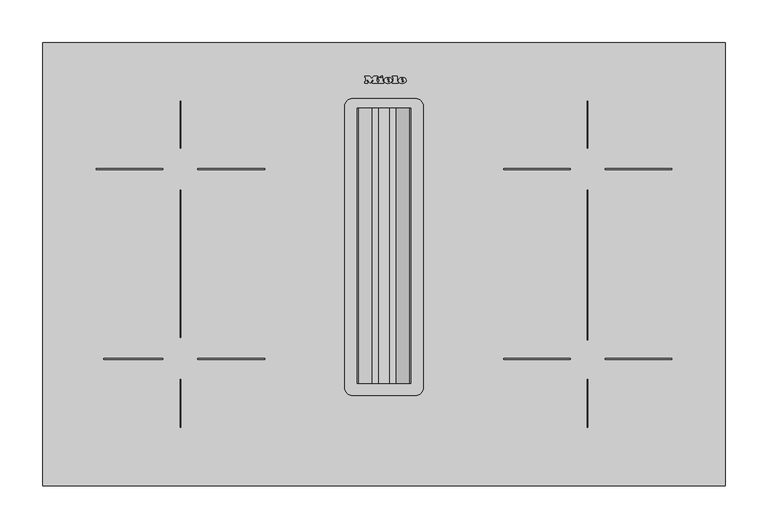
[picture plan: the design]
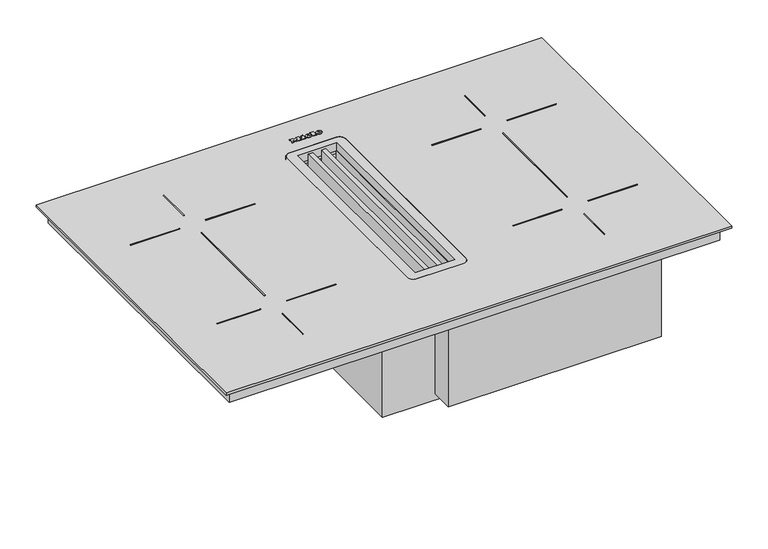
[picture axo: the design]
"""IFC4 building model written with IfcOpenShell, lengths in millimetres: proxy geometry."""

from ifc_helpers import new_model, si_unit, point, frame, frame_2d, origin, origin_with_axes, place, context, project, spatial, polyline, circle_curve, ellipse_curve, trimmed, segment, composite_curve, outline, extrude, faceted_brep, source, transform, mapped, element, save
from ifc_brep_helpers import plane_surface, cylinder_surface, revolved_surface, extruded_surface, advanced_brep


def specialty_equipment_16687752(model_context):
    return source(origin(), model_context, "Body", "SolidModel", [
        advanced_brep(
        [(20.8243124, 474.5406203, 5.0), (20.8243124, 475.3486203, 5.0), (26.1763124, 475.3486203, 5.0), (16.8643124, 475.3486203, 5.0), (19.0643124, 472.6446203, 5.0), (26.0403124, 474.5406203, 5.0), (23.6243124, 474.5406203, 5.0), (21.7203124, 473.6446203, 5.0), (20.8243124, 476.3726203, 5.0), (20.8243124, 477.2446203, 5.0), (22.1923124, 477.2446203, 5.0), (22.1923124, 476.3726203, 5.0), (20.8243124, 474.5406203, 4.0), (21.7203124, 473.6446203, 4.0), (23.6243124, 474.5406203, 4.0), (26.0403124, 474.5406203, 4.0), (19.0643124, 472.6446203, 4.0), (16.8643124, 475.3486203, 4.0), (26.1763124, 475.3486203, 4.0), (20.8243124, 475.3486203, 4.0), (20.8243124, 476.3726203, 4.0), (22.1923124, 476.3726203, 4.0), (22.1923124, 477.2446203, 4.0), (20.8243124, 477.2446203, 4.0)],
        [
            (0, 1),
            (1, 2),
            (2, 3, ellipse_curve(frame((21.5203124, 475.3486203, 5.0), z_axis=(0.0, 0.0, 1.0), x_axis=(-1.0, 0.0, 0.0)), 4.656, 3.848)),
            (3, 4, circle_curve(frame((19.960356, 475.6206203, 5.0), z_axis=(0.0, 0.0, 1.0), x_axis=(0.0, -1.0, 0.0)), 3.1079688)),
            (4, 5, circle_curve(frame((21.4271059, 477.7326203, 5.0), z_axis=(0.0, 0.0, 1.0), x_axis=(0.0, -1.0, 0.0)), 5.6098607)),
            (5, 6),
            (6, 7, circle_curve(frame((22.1113712, 475.2846203, 5.0), z_axis=(0.0, 0.0, -1.0), x_axis=(0.0, -1.0, 0.0)), 1.6859795)),
            (7, 0, circle_curve(frame((21.7203124, 474.5406203, 5.0), z_axis=(0.0, 0.0, -1.0), x_axis=(0.0, -1.0, 0.0)), 0.896)),
            (8, 9),
            (9, 10, circle_curve(frame((21.5083124, 477.2446203, 5.0), z_axis=(0.0, 0.0, -1.0), x_axis=(0.0, -1.0, 0.0)), 0.684)),
            (10, 11),
            (11, 8),
            (12, 13, circle_curve(frame((21.7203124, 474.5406203, 4.0), z_axis=(0.0, 0.0, 1.0), x_axis=(0.0, -1.0, 0.0)), 0.896)),
            (13, 14, circle_curve(frame((22.1113712, 475.2846203, 4.0), z_axis=(0.0, 0.0, 1.0), x_axis=(0.0, -1.0, 0.0)), 1.6859795)),
            (14, 15),
            (15, 16, circle_curve(frame((21.4271059, 477.7326203, 4.0), z_axis=(0.0, 0.0, -1.0), x_axis=(0.0, -1.0, 0.0)), 5.6098607)),
            (16, 17, circle_curve(frame((19.960356, 475.6206203, 4.0), z_axis=(0.0, 0.0, -1.0), x_axis=(0.0, -1.0, 0.0)), 3.1079688)),
            (17, 18, ellipse_curve(frame((21.5203124, 475.3486203, 4.0), z_axis=(0.0, 0.0, -1.0), x_axis=(-1.0, 0.0, 0.0)), 4.656, 3.848)),
            (18, 19),
            (19, 12),
            (20, 21),
            (21, 22),
            (22, 23, circle_curve(frame((21.5083124, 477.2446203, 4.0), z_axis=(0.0, 0.0, 1.0), x_axis=(0.0, -1.0, 0.0)), 0.684)),
            (23, 20),
            (0, 12),
            (19, 1),
            (18, 2),
            (5, 15),
            (14, 6),
            (17, 3),
            (13, 7),
            (16, 4),
            (8, 20),
            (23, 9),
            (22, 10),
            (21, 11),
        ],
        [
            plane_surface(frame((20.8243124, 475.3486203, 5.0), z_axis=(0.0, 0.0, 1.0), x_axis=(0.0, 1.0, 0.0))),
            plane_surface(frame((20.8243124, 475.3486203, 4.0), z_axis=(0.0, 0.0, -1.0), x_axis=(0.0, -1.0, 0.0))),
            plane_surface(frame((20.8243124, 474.5406203, 5.0), z_axis=(1.0, 0.0, 0.0), x_axis=(0.0, 0.0, -1.0))),
            plane_surface(frame((20.8243124, 475.3486203, 5.0), z_axis=(0.0, -1.0, 0.0), x_axis=(0.0, 0.0, -1.0))),
            plane_surface(frame((26.0403124, 474.5406203, 5.0), z_axis=(0.0, 1.0, 0.0), x_axis=(0.0, 0.0, -1.0))),
            extruded_surface(trimmed(ellipse_curve(frame((21.5203124, 475.3486203, 3.0), z_axis=(0.0, 0.0, 1.0), x_axis=(-1.0, 0.0, 0.0)), 4.656, 3.848), [point((26.1763124, 475.3486203, 3.0))], [point((16.8643124, 475.3486203, 3.0))], True, "CARTESIAN"), (0.0, 0.0, 1.0), 1.0),
            revolved_surface(polyline([(22.1113712, 473.5986408, 4.0), (22.1113712, 473.5986408, 5.0)]), (22.1113712, 475.2846203, 4.0), (0.0, 0.0, -1.0)),
            revolved_surface(polyline([(21.7203124, 473.6446203, 4.0), (21.7203124, 473.6446203, 5.0)]), (21.7203124, 474.5406203, 4.0), (0.0, 0.0, -1.0)),
            cylinder_surface(frame((19.960356, 475.6206203, 4.0), z_axis=(0.0, 0.0, 1.0), x_axis=(0.0, -1.0, 0.0)), 3.1079688),
            cylinder_surface(frame((21.4271059, 477.7326203, 4.0), z_axis=(0.0, 0.0, 1.0), x_axis=(0.0, -1.0, 0.0)), 5.6098607),
            plane_surface(frame((20.8243124, 476.3726203, 5.0), z_axis=(1.0, 0.0, 0.0), x_axis=(0.0, 0.0, -1.0))),
            revolved_surface(polyline([(21.5083124, 476.5606203, 4.0), (21.5083124, 476.5606203, 5.0)]), (21.5083124, 477.2446203, 4.0), (0.0, 0.0, -1.0)),
            plane_surface(frame((22.1923124, 477.2446203, 5.0), z_axis=(-1.0, 0.0, 0.0), x_axis=(0.0, 0.0, -1.0))),
            plane_surface(frame((22.1923124, 476.3726203, 5.0), z_axis=(0.0, 1.0, 0.0), x_axis=(0.0, 0.0, -1.0))),
        ],
        [
            (0, [[1, 2, 3, 4, 5, 6, 7, 8], [9, 10, 11, 12]]),
            (1, [[13, 14, 15, 16, 17, 18, 19, 20], [21, 22, 23, 24]]),
            (2, [[-1, 25, -20, 26]]),
            (3, [[-2, -26, -19, 27]]),
            (4, [[-6, 28, -15, 29]]),
            (5, [[-3, -27, -18, 30]]),
            (6, [[-7, -29, -14, 31]]),
            (7, [[-8, -31, -13, -25]]),
            (8, [[-4, -30, -17, 32]]),
            (9, [[-5, -32, -16, -28]]),
            (10, [[-9, 33, -24, 34]]),
            (11, [[-10, -34, -23, 35]]),
            (12, [[-11, -35, -22, 36]]),
            (13, [[-12, -36, -21, -33]]),
        ],
    ),
        advanced_brep(
        [(4.1283124, 474.5406203, 5.0), (4.1283124, 475.3486203, 5.0), (9.4803124, 475.3486203, 5.0), (0.1683124, 475.3486203, 5.0), (2.3683124, 472.6446203, 5.0), (9.3443124, 474.5406203, 5.0), (6.9283124, 474.5406203, 5.0), (5.0243124, 473.6446203, 5.0), (4.1283124, 476.3726203, 5.0), (4.1283124, 477.2446203, 5.0), (5.4963124, 477.2446203, 5.0), (5.4963124, 476.3726203, 5.0), (4.1283124, 474.5406203, 4.0), (5.0243124, 473.6446203, 4.0), (6.9283124, 474.5406203, 4.0), (9.3443124, 474.5406203, 4.0), (2.3683124, 472.6446203, 4.0), (0.1683124, 475.3486203, 4.0), (9.4803124, 475.3486203, 4.0), (4.1283124, 475.3486203, 4.0), (4.1283124, 476.3726203, 4.0), (5.4963124, 476.3726203, 4.0), (5.4963124, 477.2446203, 4.0), (4.1283124, 477.2446203, 4.0)],
        [
            (0, 1),
            (1, 2),
            (2, 3, ellipse_curve(frame((4.8243124, 475.3486203, 5.0), z_axis=(0.0, 0.0, 1.0), x_axis=(-1.0, 0.0, 0.0)), 4.656, 3.848)),
            (3, 4, circle_curve(frame((3.264356, 475.6206203, 5.0), z_axis=(0.0, 0.0, 1.0), x_axis=(0.0, -1.0, 0.0)), 3.1079688)),
            (4, 5, circle_curve(frame((4.7311059, 477.7326203, 5.0), z_axis=(0.0, 0.0, 1.0), x_axis=(0.0, -1.0, 0.0)), 5.6098607)),
            (5, 6),
            (6, 7, circle_curve(frame((5.4153712, 475.2846203, 5.0), z_axis=(0.0, 0.0, -1.0), x_axis=(0.0, -1.0, 0.0)), 1.6859795)),
            (7, 0, circle_curve(frame((5.0243124, 474.5406203, 5.0), z_axis=(0.0, 0.0, -1.0), x_axis=(0.0, -1.0, 0.0)), 0.896)),
            (8, 9),
            (9, 10, circle_curve(frame((4.8123124, 477.2446203, 5.0), z_axis=(0.0, 0.0, -1.0), x_axis=(0.0, -1.0, 0.0)), 0.684)),
            (10, 11),
            (11, 8),
            (12, 13, circle_curve(frame((5.0243124, 474.5406203, 4.0), z_axis=(0.0, 0.0, 1.0), x_axis=(0.0, -1.0, 0.0)), 0.896)),
            (13, 14, circle_curve(frame((5.4153712, 475.2846203, 4.0), z_axis=(0.0, 0.0, 1.0), x_axis=(0.0, -1.0, 0.0)), 1.6859795)),
            (14, 15),
            (15, 16, circle_curve(frame((4.7311059, 477.7326203, 4.0), z_axis=(0.0, 0.0, -1.0), x_axis=(0.0, -1.0, 0.0)), 5.6098607)),
            (16, 17, circle_curve(frame((3.264356, 475.6206203, 4.0), z_axis=(0.0, 0.0, -1.0), x_axis=(0.0, -1.0, 0.0)), 3.1079688)),
            (17, 18, ellipse_curve(frame((4.8243124, 475.3486203, 4.0), z_axis=(0.0, 0.0, -1.0), x_axis=(-1.0, 0.0, 0.0)), 4.656, 3.848)),
            (18, 19),
            (19, 12),
            (20, 21),
            (21, 22),
            (22, 23, circle_curve(frame((4.8123124, 477.2446203, 4.0), z_axis=(0.0, 0.0, 1.0), x_axis=(0.0, -1.0, 0.0)), 0.684)),
            (23, 20),
            (0, 12),
            (19, 1),
            (18, 2),
            (5, 15),
            (14, 6),
            (17, 3),
            (13, 7),
            (16, 4),
            (8, 20),
            (23, 9),
            (22, 10),
            (21, 11),
        ],
        [
            plane_surface(frame((4.1283124, 475.3486203, 5.0), z_axis=(0.0, 0.0, 1.0), x_axis=(0.0, 1.0, 0.0))),
            plane_surface(frame((4.1283124, 475.3486203, 4.0), z_axis=(0.0, 0.0, -1.0), x_axis=(0.0, -1.0, 0.0))),
            plane_surface(frame((4.1283124, 474.5406203, 5.0), z_axis=(1.0, 0.0, 0.0), x_axis=(0.0, 0.0, -1.0))),
            plane_surface(frame((4.1283124, 475.3486203, 5.0), z_axis=(0.0, -1.0, 0.0), x_axis=(0.0, 0.0, -1.0))),
            plane_surface(frame((9.3443124, 474.5406203, 5.0), z_axis=(0.0, 1.0, 0.0), x_axis=(0.0, 0.0, -1.0))),
            extruded_surface(trimmed(ellipse_curve(frame((4.8243124, 475.3486203, 3.0), z_axis=(0.0, 0.0, 1.0), x_axis=(-1.0, 0.0, 0.0)), 4.656, 3.848), [point((9.4803124, 475.3486203, 3.0))], [point((0.1683124, 475.3486203, 3.0))], True, "CARTESIAN"), (0.0, 0.0, 1.0), 1.0),
            revolved_surface(polyline([(5.4153712, 473.5986408, 4.0), (5.4153712, 473.5986408, 5.0)]), (5.4153712, 475.2846203, 4.0), (0.0, 0.0, -1.0)),
            revolved_surface(polyline([(5.0243124, 473.6446203, 4.0), (5.0243124, 473.6446203, 5.0)]), (5.0243124, 474.5406203, 4.0), (0.0, 0.0, -1.0)),
            cylinder_surface(frame((3.264356, 475.6206203, 4.0), z_axis=(0.0, 0.0, 1.0), x_axis=(0.0, -1.0, 0.0)), 3.1079688),
            cylinder_surface(frame((4.7311059, 477.7326203, 4.0), z_axis=(0.0, 0.0, 1.0), x_axis=(0.0, -1.0, 0.0)), 5.6098607),
            plane_surface(frame((4.1283124, 476.3726203, 5.0), z_axis=(1.0, 0.0, 0.0), x_axis=(0.0, 0.0, -1.0))),
            revolved_surface(polyline([(4.8123124, 476.5606203, 4.0), (4.8123124, 476.5606203, 5.0)]), (4.8123124, 477.2446203, 4.0), (0.0, 0.0, -1.0)),
            plane_surface(frame((5.4963124, 477.2446203, 5.0), z_axis=(-1.0, 0.0, 0.0), x_axis=(0.0, 0.0, -1.0))),
            plane_surface(frame((5.4963124, 476.3726203, 5.0), z_axis=(0.0, 1.0, 0.0), x_axis=(0.0, 0.0, -1.0))),
        ],
        [
            (0, [[1, 2, 3, 4, 5, 6, 7, 8], [9, 10, 11, 12]]),
            (1, [[13, 14, 15, 16, 17, 18, 19, 20], [21, 22, 23, 24]]),
            (2, [[-1, 25, -20, 26]]),
            (3, [[-2, -26, -19, 27]]),
            (4, [[-6, 28, -15, 29]]),
            (5, [[-3, -27, -18, 30]]),
            (6, [[-7, -29, -14, 31]]),
            (7, [[-8, -31, -13, -25]]),
            (8, [[-4, -30, -17, 32]]),
            (9, [[-5, -32, -16, -28]]),
            (10, [[-9, 33, -24, 34]]),
            (11, [[-10, -34, -23, 35]]),
            (12, [[-11, -35, -22, 36]]),
            (13, [[-12, -36, -21, -33]]),
        ],
    ),
        extrude(outline(polyline([(-4.6156876, 480.1726203), (-1.8956876, 481.4366203), (-1.2956876, 480.1406203), (-4.0076876, 478.8766203), (-4.6156876, 480.1726203)])), frame((0.0, 0.0, 4.0), z_axis=(0.0, 0.0, 1.0), x_axis=(1.0, 0.0, 0.0)), (0.0, 0.0, 1.0), 1.0),
        extrude(outline(polyline([(-6.5916876, 478.7006203), (-1.2076876, 478.7006203), (-1.2076876, 473.9886203), (-0.2796876, 473.9886203), (-0.2796876, 472.6446203), (-6.5916876, 472.6446203), (-6.5916876, 473.9886203), (-5.6396876, 473.9886203), (-5.6396876, 477.2686203), (-6.5916876, 477.2686203), (-6.5916876, 478.7006203)])), frame((0.0, 0.0, 4.0), z_axis=(0.0, 0.0, 1.0), x_axis=(1.0, 0.0, 0.0)), (0.0, 0.0, 1.0), 1.0),
        extrude(outline(polyline([(9.9283124, 479.3406203), (9.9283124, 480.6446203), (15.4323124, 480.6446203), (15.4323124, 473.9886203), (16.4163124, 473.9886203), (16.4163124, 472.6446203), (9.9283124, 472.6446203), (9.9283124, 473.9886203), (10.8883124, 473.9886203), (10.8883124, 479.3406203), (9.9283124, 479.3406203)])), frame((0.0, 0.0, 4.0), z_axis=(0.0, 0.0, 1.0), x_axis=(1.0, 0.0, 0.0)), (0.0, 0.0, 1.0), 1.0),
        extrude(outline(polyline([(-22.5356876, 479.3406203), (-22.5356876, 480.6446203), (-16.9596876, 480.6446203), (-14.6156876, 477.6446203), (-12.2796876, 480.6446203), (-7.4076876, 480.6446203), (-7.4076876, 479.3406203), (-8.4236876, 479.3406203), (-8.4236876, 473.9886203), (-7.4076876, 473.9886203), (-7.4076876, 472.6446203), (-13.7916876, 472.6446203), (-13.7916876, 473.9886203), (-12.8076876, 473.9886203), (-12.8076876, 477.4598426), (-16.3996876, 472.6446203), (-19.9756876, 477.3917451), (-19.9756876, 473.9886203), (-19.0156876, 473.9886203), (-19.0156876, 472.6446203), (-22.5356876, 472.6446203), (-22.5356876, 473.9886203), (-21.5676876, 473.9886203), (-21.5676876, 479.3406203), (-22.5356876, 479.3406203)])), frame((0.0, 0.0, 4.0), z_axis=(0.0, 0.0, 1.0), x_axis=(1.0, 0.0, 0.0)), (0.0, 0.0, 1.0), 1.0),
        faceted_brep([(-71.7186221, 460.5236466, -23.0), (-364.8972461, 460.5236466, -23.0), (-364.8972461, 59.427471, -23.0), (-71.7186221, 59.427471, -23.0), (-71.7186221, 59.427471, -49.8134964), (-364.8972461, 59.427471, -49.8134964), (-364.8972461, 460.5236466, -49.8134964), (-86.144412, 460.5236466, -49.8134964), (-86.144412, 352.5236466, -49.8134964), (-71.7186221, 352.5236466, -49.8134964), (-71.7186221, 460.5236466, -31.728133), (-86.144412, 460.5236466, -31.728133), (-71.7186221, 352.5236466, -31.728133), (-86.144412, 352.5236466, -31.728133)], [[[0, 1, 2, 3]], [[4, 5, 6, 7, 8, 9]], [[1, 0, 10, 11, 7, 6]], [[2, 1, 6, 5]], [[3, 2, 5, 4]], [[0, 3, 4, 9, 12, 10]], [[8, 13, 12, 9]], [[12, 13, 11, 10]], [[13, 8, 7, 11]]]),
        extrude(outline(polyline([(388.0, 508.0), (388.0, 12.0), (-388.0, 12.0), (-388.0, 508.0), (388.0, 508.0)]), holes=[composite_curve([segment(trimmed(circle_curve(frame_2d((36.5, 115.5)), 9.5), [point((36.5, 106.0))], [point((46.0, 115.5))], True, "CARTESIAN"), True, "CONTINUOUS"), segment(polyline([(46.0, 115.5), (46.0, 445.0)]), True, "CONTINUOUS"), segment(trimmed(circle_curve(frame_2d((36.5, 445.0)), 9.5), [point((46.0, 445.0))], [point((36.5, 454.5))], True, "CARTESIAN"), True, "CONTINUOUS"), segment(polyline([(36.5, 454.5), (-36.5395335, 454.5)]), True, "CONTINUOUS"), segment(trimmed(circle_curve(frame_2d((-36.5395335, 445.0395335)), 9.4604665), [point((-36.5395335, 454.5))], [point((-46.0, 445.0395335))], True, "CARTESIAN"), True, "CONTINUOUS"), segment(polyline([(-46.0, 445.0395335), (-46.0, 115.5)]), True, "CONTINUOUS"), segment(trimmed(circle_curve(frame_2d((-36.5, 115.5)), 9.5), [point((-46.0, 115.5))], [point((-36.5, 106.0))], True, "CARTESIAN"), True, "CONTINUOUS"), segment(polyline([(-36.5, 106.0), (36.5, 106.0)]), True, "CONTINUOUS")], self_intersect=False)]), frame((0.0, 0.0, -23.0), z_axis=(0.0, 0.0, 1.0), x_axis=(1.0, 0.0, 0.0)), (0.0, 0.0, 1.0), 23.0),
        extrude(outline(polyline([(400.0, 520.0), (400.0, 0.0), (-400.0, 0.0), (-400.0, 520.0), (400.0, 520.0)]), holes=[composite_curve([segment(polyline([(36.5, 454.5), (-36.5, 454.5)]), True, "CONTINUOUS"), segment(trimmed(circle_curve(frame_2d((-36.5, 445.0)), 9.5), [point((-36.5, 454.5))], [point((-46.0, 445.0))], True, "CARTESIAN"), True, "CONTINUOUS"), segment(polyline([(-46.0, 445.0), (-46.0, 115.5)]), True, "CONTINUOUS"), segment(trimmed(circle_curve(frame_2d((-36.5, 115.5)), 9.5), [point((-46.0, 115.5))], [point((-36.5, 106.0))], True, "CARTESIAN"), True, "CONTINUOUS"), segment(polyline([(-36.5, 106.0), (36.5, 106.0)]), True, "CONTINUOUS"), segment(trimmed(circle_curve(frame_2d((36.5, 115.5)), 9.5), [point((36.5, 106.0))], [point((46.0, 115.5))], True, "CARTESIAN"), True, "CONTINUOUS"), segment(polyline([(46.0, 115.5), (46.0, 445.0)]), True, "CONTINUOUS"), segment(trimmed(circle_curve(frame_2d((36.5, 445.0)), 9.5), [point((46.0, 445.0))], [point((36.5, 454.5))], True, "CARTESIAN"), True, "CONTINUOUS")], self_intersect=False)]), origin_with_axes(), (0.0, 0.0, 1.0), 4.0),
        extrude(outline(polyline([(-45.5823584, -70.2509053), (-35.5367274, -70.2509053), (-35.5367274, -77.4712026), (-36.7924312, -77.4712026), (-36.7924312, -71.5066091), (-39.7747279, -71.5066091), (-39.7747279, -77.1572766), (-41.0304318, -77.1572766), (-41.0304318, -71.5066091), (-44.3266545, -71.5066091), (-44.3266545, -77.6281655), (-45.5823584, -77.6281655), (-45.5823584, -70.2509053)])), frame((0.0, 405.5236466, 0.0), z_axis=(0.0, 1.0, 0.0), x_axis=(0.0, 0.0, 1.0)), (0.0, 0.0, 1.0), 1.0),
        extrude(outline(polyline([(-45.5823584, -79.5117214), (-35.5367274, -79.5117214), (-35.5367274, -80.7674252), (-44.3266545, -80.7674252), (-44.3266545, -85.7902407), (-45.5823584, -85.7902407), (-45.5823584, -79.5117214)])), frame((0.0, 405.5236466, 0.0), z_axis=(0.0, 1.0, 0.0), x_axis=(0.0, 0.0, 1.0)), (0.0, 0.0, 1.0), 1.0),
        extrude(outline(polyline([(-238.0, 347.0), (-238.0, 174.0), (-239.0, 174.0), (-239.0, 347.0), (-238.0, 347.0)])), frame((0.0, 0.0, 5.0), z_axis=(0.0, 0.0, 1.0), x_axis=(1.0, 0.0, 0.0)), (0.0, 0.0, 1.0), 1.0),
        extrude(outline(polyline([(238.0, 347.0), (239.0, 347.0), (239.0, 171.2818617), (238.0, 171.2818617), (238.0, 347.0)])), frame((0.0, 0.0, 5.0), z_axis=(0.0, 0.0, 1.0), x_axis=(1.0, 0.0, 0.0)), (0.0, 0.0, 1.0), 1.0),
        advanced_brep(
        [(-86.144412, 370.5236466, -40.8134964), (-86.144412, 380.5236466, -40.8134964), (-71.144412, 370.5236466, -40.8134964), (-81.144412, 380.5236466, -40.8134964), (-71.144412, 405.5236466, -40.8134964), (-81.144412, 405.5236466, -40.8134964)],
        [
            (0, 1, circle_curve(frame((-86.144412, 375.5236466, -40.8134964), z_axis=(-1.0, 0.0, 0.0), x_axis=(0.0, 1.0, 0.0)), 5.0)),
            (1, 0, circle_curve(frame((-86.144412, 375.5236466, -40.8134964), z_axis=(-1.0, 0.0, 0.0), x_axis=(0.0, 1.0, 0.0)), 5.0)),
            (0, 2),
            (2, 3, ellipse_curve(frame((-76.144412, 375.5236466, -40.8134964), z_axis=(-0.7071067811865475, -0.7071067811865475, 0.0), x_axis=(-0.7071067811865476, 0.7071067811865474, 0.0)), 7.0710678, 5.0)),
            (3, 1),
            (3, 2, ellipse_curve(frame((-76.144412, 375.5236466, -40.8134964), z_axis=(-0.7071067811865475, -0.7071067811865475, 0.0), x_axis=(-0.7071067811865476, 0.7071067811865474, 0.0)), 7.0710678, 5.0)),
            (4, 5, circle_curve(frame((-76.144412, 405.5236466, -40.8134964), z_axis=(0.0, 1.0, 0.0), x_axis=(-1.0, 0.0, 0.0)), 5.0)),
            (5, 4, circle_curve(frame((-76.144412, 405.5236466, -40.8134964), z_axis=(0.0, 1.0, 0.0), x_axis=(-1.0, 0.0, 0.0)), 5.0)),
            (2, 4),
            (5, 3),
        ],
        [
            plane_surface(frame((-86.144412, 375.5236466, 0.0), z_axis=(-1.0, 0.0, 0.0), x_axis=(0.0, 0.0, 1.0))),
            cylinder_surface(frame((-86.144412, 375.5236466, -40.8134964), z_axis=(-1.0, 0.0, 0.0), x_axis=(0.0, 1.0, 0.0)), 5.0),
            plane_surface(frame((-76.144412, 405.5236466, 0.0), z_axis=(0.0, 1.0, 0.0), x_axis=(0.0, 0.0, 1.0))),
            cylinder_surface(frame((-76.144412, 375.5236466, -40.8134964), z_axis=(0.0, -1.0, 0.0), x_axis=(-1.0, 0.0, 0.0)), 5.0),
        ],
        [
            (0, [[1, 2]]),
            (1, [[-1, 3, 4, 5]]),
            (1, [[-2, -5, 6, -3]]),
            (2, [[7, 8]]),
            (3, [[-4, 9, -8, 10]]),
            (3, [[-6, -10, -7, -9]]),
        ],
    ),
        extrude(outline(polyline([(-259.0, 372.0), (-259.0, 371.0), (-337.0, 371.0), (-337.0, 372.0), (-259.0, 372.0)])), frame((0.0, 0.0, 4.0), z_axis=(0.0, 0.0, 1.0), x_axis=(1.0, 0.0, 0.0)), (0.0, 0.0, 1.0), 1.0),
        extrude(outline(polyline([(-140.0, 372.0), (-140.0, 371.0), (-218.0, 371.0), (-218.0, 372.0), (-140.0, 372.0)])), frame((0.0, 0.0, 4.0), z_axis=(0.0, 0.0, 1.0), x_axis=(1.0, 0.0, 0.0)), (0.0, 0.0, 1.0), 1.0),
        extrude(outline(polyline([(-259.0, 148.7), (-328.4422621, 148.7), (-328.4422621, 149.7), (-259.0, 149.7), (-259.0, 148.7)])), frame((0.0, 0.0, 4.0), z_axis=(0.0, 0.0, 1.0), x_axis=(1.0, 0.0, 0.0)), (0.0, 0.0, 1.0), 1.0),
        extrude(outline(polyline([(-140.0, 149.7), (-140.0, 148.7), (-218.0, 148.7), (-218.0, 149.7), (-140.0, 149.7)])), frame((0.0, 0.0, 4.0), z_axis=(0.0, 0.0, 1.0), x_axis=(1.0, 0.0, 0.0)), (0.0, 0.0, 1.0), 1.0),
        extrude(outline(polyline([(259.0, 372.0), (337.0, 372.0), (337.0, 371.0), (259.0, 371.0), (259.0, 372.0)])), frame((0.0, 0.0, 4.0), z_axis=(0.0, 0.0, 1.0), x_axis=(1.0, 0.0, 0.0)), (0.0, 0.0, 1.0), 1.0),
        extrude(outline(polyline([(140.5, 372.0), (218.0, 372.0), (218.0, 371.0), (140.5, 371.0), (140.5, 372.0)])), frame((0.0, 0.0, 4.0), z_axis=(0.0, 0.0, 1.0), x_axis=(1.0, 0.0, 0.0)), (0.0, 0.0, 1.0), 1.0),
        extrude(outline(polyline([(-239.0, 68.5), (-239.0, 125.0), (-238.0, 125.0), (-238.0, 68.5), (-239.0, 68.5)])), frame((0.0, 0.0, 4.0), z_axis=(0.0, 0.0, 1.0), x_axis=(1.0, 0.0, 0.0)), (0.0, 0.0, 1.0), 1.0),
        extrude(outline(polyline([(239.0, 69.0), (238.0, 69.0), (238.0, 125.0), (239.0, 125.0), (239.0, 69.0)])), frame((0.0, 0.0, 4.0), z_axis=(0.0, 0.0, 1.0), x_axis=(1.0, 0.0, 0.0)), (0.0, 0.0, 1.0), 1.0),
        extrude(outline(polyline([(239.0, 451.5), (239.0, 396.0), (238.0, 396.0), (238.0, 451.5), (239.0, 451.5)])), frame((0.0, 0.0, 4.0), z_axis=(0.0, 0.0, 1.0), x_axis=(1.0, 0.0, 0.0)), (0.0, 0.0, 1.0), 1.0),
        extrude(outline(polyline([(-239.0, 451.5), (-238.0, 451.5), (-238.0, 396.0), (-239.0, 396.0), (-239.0, 451.5)])), frame((0.0, 0.0, 4.0), z_axis=(0.0, 0.0, 1.0), x_axis=(1.0, 0.0, 0.0)), (0.0, 0.0, 1.0), 1.0),
        extrude(outline(polyline([(259.0, 148.7), (259.0, 149.7), (337.0, 149.7), (337.0, 148.7), (259.0, 148.7)])), frame((0.0, 0.0, 4.0), z_axis=(0.0, 0.0, 1.0), x_axis=(1.0, 0.0, 0.0)), (0.0, 0.0, 1.0), 1.0),
        extrude(outline(polyline([(140.5, 148.7), (140.5, 149.7), (218.0, 149.7), (218.0, 148.7), (140.5, 148.7)])), frame((0.0, 0.0, 4.0), z_axis=(0.0, 0.0, 1.0), x_axis=(1.0, 0.0, 0.0)), (0.0, 0.0, 1.0), 1.0),
        extrude(outline(polyline([(14.0, 120.177901), (7.0, 120.177901), (7.0, 443.3010247), (14.0, 443.3010247), (14.0, 120.177901)])), frame((0.0, 0.0, -30.0), z_axis=(0.0, 0.0, 1.0), x_axis=(1.0, 0.0, 0.0)), (0.0, 0.0, 1.0), 30.0),
        extrude(outline(polyline([(-7.0, 120.177901), (-14.0, 120.177901), (-14.0, 443.3010247), (-7.0, 443.3010247), (-7.0, 120.177901)])), frame((0.0, 0.0, -30.0), z_axis=(0.0, 0.0, 1.0), x_axis=(1.0, 0.0, 0.0)), (0.0, 0.0, 1.0), 30.0),
        extrude(outline(polyline([(-150.3933796, 8.7812172), (-23.0, 31.0806576), (-9.6002538, 31.0806576), (-9.6002538, 30.0806576), (-22.9176, 30.0806576), (-149.3933796, 7.9334714), (-149.3933796, -10.4294884), (-23.1226136, -30.0513858), (-9.6002538, -30.0513858), (-9.6002538, -31.0802193), (-23.0, -31.0802193), (-150.3933796, -11.2930358), (-150.3933796, 8.7812172)])), frame((0.0, 120.177901, 0.0), z_axis=(0.0, 1.0, 0.0), x_axis=(0.0, 0.0, 1.0)), (0.0, 0.0, 1.0), 323.1231238),
        advanced_brep(
        [(65.0, 90.0, -196.0003671), (65.0, 90.0, -23.0), (-55.0, 90.0, -23.0), (-58.0, 90.0, -26.0), (-58.0, 90.0, -78.0), (-97.8585744, 90.0, -78.0), (-100.8585744, 90.0, -81.0), (-100.8585744, 90.0, -196.0003671), (65.0, 473.0, -196.0003671), (-100.8585744, 473.0, -196.0003671), (-100.8585744, 473.0, -81.0), (-97.8585744, 473.0, -78.0), (-58.0, 473.0, -78.0), (-58.0, 473.0, -26.0), (-55.0, 473.0, -23.0), (65.0, 473.0, -23.0), (-31.0802193, 443.3010247, -23.0), (31.0806576, 443.3010247, -23.0), (31.0806576, 120.177901, -23.0), (-31.0802193, 120.177901, -23.0), (31.0806576, 443.3010247, -150.3933796), (-31.0802193, 443.3010247, -150.3933796), (-31.0802193, 120.177901, -150.3933796), (31.0806576, 120.177901, -150.3933796)],
        [
            (0, 1),
            (1, 2),
            (2, 3, circle_curve(frame((-55.0, 90.0, -26.0), z_axis=(0.0, -1.0, 0.0), x_axis=(1.0, 0.0, 0.0)), 3.0)),
            (3, 4),
            (4, 5),
            (5, 6, circle_curve(frame((-97.8585744, 90.0, -81.0), z_axis=(0.0, -1.0, 0.0), x_axis=(1.0, 0.0, 0.0)), 3.0)),
            (6, 7),
            (7, 0),
            (8, 9),
            (9, 10),
            (10, 11, circle_curve(frame((-97.8585744, 473.0, -81.0), z_axis=(0.0, 1.0, 0.0), x_axis=(1.0, 0.0, 0.0)), 3.0)),
            (11, 12),
            (12, 13),
            (13, 14, circle_curve(frame((-55.0, 473.0, -26.0), z_axis=(0.0, 1.0, 0.0), x_axis=(1.0, 0.0, 0.0)), 3.0)),
            (14, 15),
            (15, 8),
            (0, 8),
            (15, 1),
            (14, 2),
            (16, 17),
            (17, 18),
            (18, 19),
            (19, 16),
            (3, 13),
            (12, 4),
            (11, 5),
            (6, 10),
            (9, 7),
            (20, 21),
            (21, 22),
            (22, 23),
            (23, 20),
            (20, 17),
            (16, 21),
            (19, 22),
            (18, 23),
        ],
        [
            plane_surface(frame((65.0, 90.0, -196.0003671), z_axis=(0.0, -1.0, 0.0), x_axis=(0.0, 0.0, 1.0))),
            plane_surface(frame((65.0, 473.0, -196.0003671), z_axis=(0.0, 1.0, 0.0), x_axis=(0.0, 0.0, -1.0))),
            plane_surface(frame((65.0, 90.0, -196.0003671), z_axis=(1.0, 0.0, 0.0), x_axis=(0.0, 1.0, 0.0))),
            plane_surface(frame((65.0, 90.0, -23.0), z_axis=(0.0, 0.0, 1.0), x_axis=(0.0, 1.0, 0.0))),
            plane_surface(frame((-58.0, 90.0, -26.0), z_axis=(-1.0, 0.0, 0.0), x_axis=(0.0, 1.0, 0.0))),
            plane_surface(frame((-58.0, 90.0, -78.0), z_axis=(0.0, 0.0, 1.0), x_axis=(0.0, 1.0, 0.0))),
            plane_surface(frame((-100.8585744, 90.0, -81.0), z_axis=(-1.0, 0.0, 0.0), x_axis=(0.0, 1.0, 0.0))),
            plane_surface(frame((-100.8585744, 90.0, -196.0003671), z_axis=(0.0, 0.0, -1.0), x_axis=(0.0, 1.0, 0.0))),
            cylinder_surface(frame((-55.0, 473.0, -26.0), z_axis=(0.0, -1.0, 0.0), x_axis=(1.0, 0.0, 0.0)), 3.0),
            cylinder_surface(frame((-97.8585744, 473.0, -81.0), z_axis=(0.0, -1.0, 0.0), x_axis=(1.0, 0.0, 0.0)), 3.0),
            plane_surface(frame((-31.0802193, 443.3010247, -150.3933796), z_axis=(0.0, 0.0, 1.0), x_axis=(1.0, 0.0, 0.0))),
            plane_surface(frame((31.0806576, 443.3010247, 0.0), z_axis=(0.0, -1.0, 0.0), x_axis=(0.0, 0.0, -1.0))),
            plane_surface(frame((-31.0802193, 443.3010247, 0.0), z_axis=(1.0, 0.0, 0.0), x_axis=(0.0, 0.0, -1.0))),
            plane_surface(frame((-31.0802193, 120.177901, 0.0), z_axis=(0.0, 1.0, 0.0), x_axis=(0.0, 0.0, -1.0))),
            plane_surface(frame((31.0806576, 120.177901, 0.0), z_axis=(-1.0, 0.0, 0.0), x_axis=(0.0, 0.0, -1.0))),
        ],
        [
            (0, [[1, 2, 3, 4, 5, 6, 7, 8]]),
            (1, [[9, 10, 11, 12, 13, 14, 15, 16]]),
            (2, [[-1, 17, -16, 18]]),
            (3, [[-2, -18, -15, 19], [20, 21, 22, 23]]),
            (4, [[-4, 24, -13, 25]]),
            (5, [[-5, -25, -12, 26]]),
            (6, [[-7, 27, -10, 28]]),
            (7, [[-8, -28, -9, -17]]),
            (8, [[-3, -19, -14, -24]]),
            (9, [[-6, -26, -11, -27]]),
            (10, [[29, 30, 31, 32]]),
            (11, [[-29, 33, -20, 34]]),
            (12, [[-30, -34, -23, 35]]),
            (13, [[-31, -35, -22, 36]]),
            (14, [[-32, -36, -21, -33]]),
        ],
    ),
        advanced_brep(
        [(-36.5, 106.0, 4.0), (36.5, 106.0, 4.0), (46.0, 115.5, 4.0), (46.0, 447.9999992, 4.0), (36.5, 457.4999992, 4.0), (-36.5, 457.4999992, 4.0), (-46.0, 447.9999992, 4.0), (-46.0, 115.5, 4.0), (31.0806576, 443.3010247, 4.0), (31.0806576, 120.177901, 4.0), (-31.0802193, 120.177901, 4.0), (-31.0802193, 443.3010247, 4.0), (-36.5, 106.0, -9.6002538), (-46.0, 115.5, -9.6002538), (-46.0, 447.9999992, -9.6002538), (-36.5, 457.4999992, -9.6002538), (36.5, 457.4999992, -9.6002538), (46.0, 447.9999992, -9.6002538), (46.0, 115.5, -9.6002538), (36.5, 106.0, -9.6002538), (31.0806576, 443.3010247, -9.6002538), (-31.0802193, 443.3010247, -9.6002538), (-31.0802193, 120.177901, -9.6002538), (31.0806576, 120.177901, -9.6002538), (31.0806576, 443.3010247, 0.0), (31.0806576, 120.177901, 0.0), (-31.0802193, 120.177901, 0.0), (-31.0802193, 443.3010247, 0.0)],
        [
            (0, 1),
            (1, 2, circle_curve(frame((36.5, 115.5, 4.0), z_axis=(0.0, 0.0, 1.0), x_axis=(1.0, 0.0, 0.0)), 9.5)),
            (2, 3),
            (3, 4, circle_curve(frame((36.5, 447.9999992, 4.0), z_axis=(0.0, 0.0, 1.0), x_axis=(1.0, 0.0, 0.0)), 9.5)),
            (4, 5),
            (5, 6, circle_curve(frame((-36.5, 447.9999992, 4.0), z_axis=(0.0, 0.0, 1.0), x_axis=(1.0, 0.0, 0.0)), 9.5)),
            (6, 7),
            (7, 0, circle_curve(frame((-36.5, 115.5, 4.0), z_axis=(0.0, 0.0, 1.0), x_axis=(1.0, 0.0, 0.0)), 9.5)),
            (8, 9),
            (9, 10),
            (10, 11),
            (11, 8),
            (12, 13, circle_curve(frame((-36.5, 115.5, -9.6002538), z_axis=(0.0, 0.0, -1.0), x_axis=(1.0, 0.0, 0.0)), 9.5)),
            (13, 14),
            (14, 15, circle_curve(frame((-36.5, 447.9999992, -9.6002538), z_axis=(0.0, 0.0, -1.0), x_axis=(1.0, 0.0, 0.0)), 9.5)),
            (15, 16),
            (16, 17, circle_curve(frame((36.5, 447.9999992, -9.6002538), z_axis=(0.0, 0.0, -1.0), x_axis=(1.0, 0.0, 0.0)), 9.5)),
            (17, 18),
            (18, 19, circle_curve(frame((36.5, 115.5, -9.6002538), z_axis=(0.0, 0.0, -1.0), x_axis=(1.0, 0.0, 0.0)), 9.5)),
            (19, 12),
            (20, 21),
            (21, 22),
            (22, 23),
            (23, 20),
            (0, 12),
            (19, 1),
            (18, 2),
            (17, 3),
            (16, 4),
            (15, 5),
            (14, 6),
            (13, 7),
            (8, 24),
            (24, 20),
            (23, 25),
            (25, 9),
            (22, 26),
            (26, 10),
            (21, 27),
            (27, 11),
        ],
        [
            plane_surface(frame((36.5, 106.0, 4.0), z_axis=(0.0, 0.0, 1.0), x_axis=(1.0, 0.0, 0.0))),
            plane_surface(frame((36.5, 106.0, -9.6002538), z_axis=(0.0, 0.0, -1.0), x_axis=(-1.0, 0.0, 0.0))),
            plane_surface(frame((-36.5, 106.0, 4.0), z_axis=(0.0, -1.0, 0.0), x_axis=(0.0, 0.0, -1.0))),
            cylinder_surface(frame((36.5, 115.5, -9.6002538), z_axis=(0.0, 0.0, 1.0), x_axis=(1.0, 0.0, 0.0)), 9.5),
            plane_surface(frame((46.0, 115.5, 4.0), z_axis=(1.0, 0.0, 0.0), x_axis=(0.0, 0.0, -1.0))),
            cylinder_surface(frame((36.5, 447.9999992, -9.6002538), z_axis=(0.0, 0.0, 1.0), x_axis=(1.0, 0.0, 0.0)), 9.5),
            plane_surface(frame((36.5, 457.4999992, 4.0), z_axis=(0.0, 1.0, 0.0), x_axis=(0.0, 0.0, -1.0))),
            cylinder_surface(frame((-36.5, 447.9999992, -9.6002538), z_axis=(0.0, 0.0, 1.0), x_axis=(1.0, 0.0, 0.0)), 9.5),
            plane_surface(frame((-46.0, 447.9999992, 4.0), z_axis=(-1.0, 0.0, 0.0), x_axis=(0.0, 0.0, -1.0))),
            cylinder_surface(frame((-36.5, 115.5, -9.6002538), z_axis=(0.0, 0.0, 1.0), x_axis=(1.0, 0.0, 0.0)), 9.5),
            plane_surface(frame((31.0806576, 443.3010247, 4.0), z_axis=(-1.0, 0.0, 0.0), x_axis=(0.0, 0.0, -1.0))),
            plane_surface(frame((31.0806576, 120.177901, 4.0), z_axis=(0.0, 1.0, 0.0), x_axis=(0.0, 0.0, -1.0))),
            plane_surface(frame((-31.0802193, 120.177901, 4.0), z_axis=(1.0, 0.0, 0.0), x_axis=(0.0, 0.0, -1.0))),
            plane_surface(frame((-31.0802193, 443.3010247, 4.0), z_axis=(0.0, -1.0, 0.0), x_axis=(0.0, 0.0, -1.0))),
        ],
        [
            (0, [[1, 2, 3, 4, 5, 6, 7, 8], [9, 10, 11, 12]]),
            (1, [[13, 14, 15, 16, 17, 18, 19, 20], [21, 22, 23, 24]]),
            (2, [[-1, 25, -20, 26]]),
            (3, [[-2, -26, -19, 27]]),
            (4, [[-3, -27, -18, 28]]),
            (5, [[-4, -28, -17, 29]]),
            (6, [[-5, -29, -16, 30]]),
            (7, [[-6, -30, -15, 31]]),
            (8, [[-7, -31, -14, 32]]),
            (9, [[-8, -32, -13, -25]]),
            (10, [[-9, 33, 34, -24, 35, 36]]),
            (11, [[-10, -36, -35, -23, 37, 38]]),
            (12, [[-11, -38, -37, -22, 39, 40]]),
            (13, [[-12, -40, -39, -21, -34, -33]]),
        ],
    ),
        extrude(outline(composite_curve([segment(trimmed(circle_curve(frame_2d((-110.1544508, 169.7588654)), 75.9996175), [point((-110.1544508, 93.7592479))], [point((-110.1544508, 245.7584828))], False, "CARTESIAN"), True, "CONTINUOUS"), segment(trimmed(circle_curve(frame_2d((-110.1544508, 169.7588654)), 75.9996175), [point((-110.1544508, 245.7584828))], [point((-110.1544508, 93.7592479))], False, "CARTESIAN"), True, "CONTINUOUS")], self_intersect=False), holes=[composite_curve([segment(trimmed(circle_curve(frame_2d((-110.1544508, 169.7588654)), 74.9996175), [point((-110.1544508, 94.7592479))], [point((-110.1544508, 244.7584828))], True, "CARTESIAN"), True, "CONTINUOUS"), segment(trimmed(circle_curve(frame_2d((-110.1544508, 169.7588654)), 74.9996175), [point((-110.1544508, 244.7584828))], [point((-110.1544508, 94.7592479))], True, "CARTESIAN"), True, "CONTINUOUS")], self_intersect=False)]), frame((0.0, 426.5236466, 0.0), z_axis=(0.0, 1.0, 0.0), x_axis=(0.0, 0.0, 1.0)), (0.0, 0.0, 1.0), 19.4763534),
        advanced_brep(
        [(240.0248541, 80.7444185, -23.0), (389.0, 174.8912467, -23.0), (389.0, 426.5236466, -23.0), (65.0, 426.5236466, -23.0), (65.0, 80.7444185, -23.0), (240.0248541, 80.7444185, -196.0003671), (65.0, 80.7444185, -196.0003671), (65.0, 426.5236466, -196.0003671), (260.0, 426.5236466, -196.0003671), (260.0, 378.7724959, -196.0003671), (389.0, 321.5236466, -196.0003671), (389.0, 174.8912467, -196.0003671), (389.0, 321.5236466, -158.2041546), (389.0, 426.5236466, -158.2041546), (260.0, 426.5236466, -158.2041546), (260.0, 378.7724959, -158.2041546)],
        [
            (0, 1, circle_curve(frame((248.2422198, 232.6818412, -23.0), z_axis=(0.0, 0.0, 1.0), x_axis=(1.0, 0.0, 0.0)), 152.1594739)),
            (1, 2),
            (2, 3),
            (3, 4),
            (4, 0),
            (5, 6),
            (6, 7),
            (7, 8),
            (8, 9),
            (9, 10, circle_curve(frame((261.4898072, 208.1659183, -196.0003671), z_axis=(0.0, 0.0, -1.0), x_axis=(1.0, 0.0, 0.0)), 170.6130823)),
            (10, 11),
            (11, 5, circle_curve(frame((248.2422198, 232.6818412, -196.0003671), z_axis=(0.0, 0.0, -1.0), x_axis=(1.0, 0.0, 0.0)), 152.1594739)),
            (0, 5),
            (11, 1),
            (10, 12),
            (12, 13),
            (13, 2),
            (13, 14),
            (14, 8),
            (7, 3),
            (6, 4),
            (12, 15, circle_curve(frame((261.4898072, 208.1659183, -158.2041546), z_axis=(0.0, 0.0, 1.0), x_axis=(1.0, 0.0, 0.0)), 170.6130823)),
            (15, 14),
            (15, 9),
        ],
        [
            plane_surface(frame((400.4016937, 232.6818412, -23.0), z_axis=(0.0, 0.0, 1.0), x_axis=(0.0, 1.0, 0.0))),
            plane_surface(frame((400.4016937, 232.6818412, -196.0003671), z_axis=(0.0, 0.0, -1.0), x_axis=(0.0, -1.0, 0.0))),
            cylinder_surface(frame((248.2422198, 232.6818412, -196.0003671), z_axis=(0.0, 0.0, 1.0), x_axis=(1.0, 0.0, 0.0)), 152.1594739),
            plane_surface(frame((389.0, 174.8912467, -23.0), z_axis=(1.0, 0.0, 0.0), x_axis=(0.0, 0.0, -1.0))),
            plane_surface(frame((389.0, 426.5236466, -23.0), z_axis=(0.0, 1.0, 0.0), x_axis=(0.0, 0.0, -1.0))),
            plane_surface(frame((65.0, 426.5236466, -23.0), z_axis=(-1.0, 0.0, 0.0), x_axis=(0.0, 0.0, -1.0))),
            plane_surface(frame((65.0, 80.7444185, -23.0), z_axis=(0.0, -1.0, 0.0), x_axis=(0.0, 0.0, -1.0))),
            plane_surface(frame((389.0, 426.5236466, -158.2041546), z_axis=(0.0, 0.0, -1.0), x_axis=(-1.0, 0.0, 0.0))),
            plane_surface(frame((260.0, 426.5236466, -158.2041546), z_axis=(1.0, 0.0, 0.0), x_axis=(0.0, 0.0, -1.0))),
            cylinder_surface(frame((261.4898072, 208.1659183, -272.677701), z_axis=(0.0, 0.0, -1.0), x_axis=(1.0, 0.0, 0.0)), 170.6130823),
        ],
        [
            (0, [[1, 2, 3, 4, 5]]),
            (1, [[6, 7, 8, 9, 10, 11, 12]]),
            (2, [[-1, 13, -12, 14]]),
            (3, [[-2, -14, -11, 15, 16, 17]]),
            (4, [[-3, -17, 18, 19, -8, 20]]),
            (5, [[-4, -20, -7, 21]]),
            (6, [[-5, -21, -6, -13]]),
            (7, [[22, 23, -18, -16]]),
            (8, [[-23, 24, -9, -19]]),
            (9, [[-22, -15, -10, -24]]),
        ],
    ),
        extrude(outline(composite_curve([segment(polyline([(319.5, 53.0), (-18.0, 53.0), (-18.0, 90.0), (234.4259817, 90.0)]), True, "CONTINUOUS"), segment(trimmed(circle_curve(frame_2d((249.106636, 239.3301036)), 150.0499965), [point((234.4259817, 90.0))], [point((319.5, 106.8167995))], True, "CARTESIAN"), True, "CONTINUOUS"), segment(polyline([(319.5, 106.8167995), (319.5, 53.0)]), True, "CONTINUOUS")], self_intersect=False)), frame((0.0, 0.0, -184.7506583), z_axis=(0.0, 0.0, 1.0), x_axis=(1.0, 0.0, 0.0)), (0.0, 0.0, 1.0), 144.8266632),
        extrude(outline(polyline([(-113.1544508, 175.3890505), (-103.1088198, 171.3791367), (-103.1088198, 170.3098264), (-113.1544508, 166.2999127), (-113.1544508, 167.6267404), (-110.0151911, 168.7769848), (-110.0151911, 172.9144309), (-113.1544508, 174.0622228), (-113.1544508, 175.3890505)]), holes=[polyline([(-108.7594872, 172.4533522), (-108.7594872, 169.235611), (-106.2897728, 170.1406007), (-104.3645237, 170.8444816), (-106.0739487, 171.469881), (-108.7594872, 172.4533522)])]), frame((0.0, 446.0, 0.0), z_axis=(0.0, 1.0, 0.0), x_axis=(0.0, 0.0, 1.0)), (0.0, 0.0, 1.0), 1.0),
        extrude(outline(polyline([(-113.1544508, 164.9583697), (-103.1088198, 164.9583697), (-103.1088198, 163.7026658), (-111.8987469, 163.7026658), (-111.8987469, 158.6798503), (-113.1544508, 158.6798503), (-113.1544508, 164.9583697)])), frame((0.0, 446.0, 0.0), z_axis=(0.0, 1.0, 0.0), x_axis=(0.0, 0.0, 1.0)), (0.0, 0.0, 1.0), 1.0),
    ])


if __name__ == "__main__":
    model = new_model("IFC4")
    model_context = context("Model", 3, world=origin())
    ifc_project = project(units=[si_unit("LENGTHUNIT", "METRE", prefix="MILLI")], contexts=[model_context])
    site = spatial("IfcSite", under=ifc_project)
    building = spatial("IfcBuilding", under=site)
    placement = place(None, origin())
    specialty_equipment_shape = specialty_equipment_16687752(model_context)
    element("IfcBuildingElementProxy", 1, Name="Specialty Equipment", at=placement, inside=building, context=model_context, shape_type="MappedRepresentation", body=[
        mapped(specialty_equipment_shape, transform((0.0, 0.0, 0.0), x_axis=(1.0, 0.0, 0.0), y_axis=(0.0, 1.0, 0.0), z_axis=(0.0, 0.0, 1.0))),
    ])
    save(model, "model.ifc")
